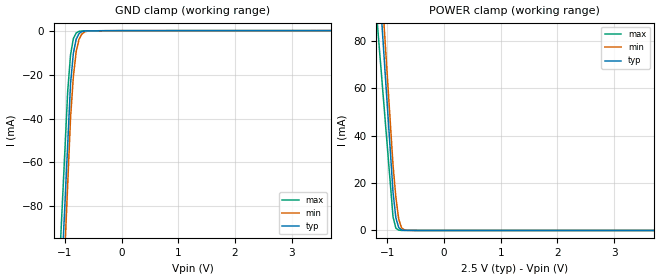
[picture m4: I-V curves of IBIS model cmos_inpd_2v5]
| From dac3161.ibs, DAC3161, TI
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[Model] cmos_inpd_2v5
Model_type Input
Vinl = 625.000mV
Vinh = 1.50000V
C_comp 865.000fF 865.000fF 865.000fF
| variable typ   min   max
[Voltage Range] 2.50000V 2.25000V 2.75000V
[POWER Clamp Reference] 2.50000V 2.25000V 2.75000V
[GND Clamp Reference] 0.00000V 0.00000V 0.00000V
[Temperature Range]   25   85   -40
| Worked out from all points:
|   GND clamp passes 1 mA (typ) near -0.73 V on its own axis
|   POWER clamp passes 1 mA (typ) near -0.79 V on its own axis
[GND Clamp]
-2.5V     -910.4mA   -1.007A    -866.3mA
-950mV    -51.81mA   -69.99mA   -27.77mA
-900mV    -24.11mA   -39.78mA   -11.07mA
-850mV    -10.28mA   -20.91mA   -3.606mA
-800mV    -3.848mA   -9.481mA   -1.049mA
-750mV    -1.297mA   -3.904mA   -310.8uA
-700mV    -414.9uA   -1.507mA   -138.7uA
-600mV    -141uA     -199.2uA   -105.3uA
5V        32.89uA    38.71uA    26.11uA
[POWER Clamp]
-2.5V     594.9mA    624.4mA    476.7mA
-1.15V    106.6mA    120.8mA    79.34mA
-1.1V     88.51mA    102.2mA    64.62mA
-1.05V    70.42mA    83.5mA     49.9mA
-900mV    16.17mA    27.55mA    5.751mA
-850mV    5.321mA    14.01mA    963.3uA
-800mV    1.275mA    4.801mA    157.9uA
-750mV    229.2uA    1.107mA    32.74uA
-700mV    51.51uA    238.1uA    29.47uA
-650mV    44.15uA    58.44uA    26.19uA
5V        0A         0A         0A
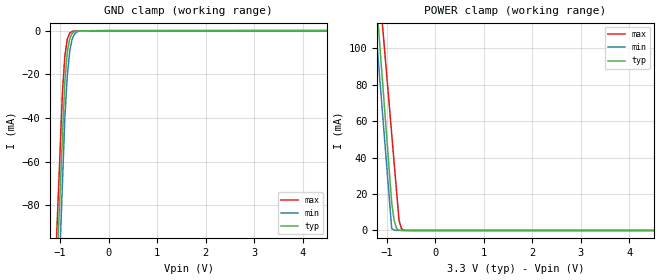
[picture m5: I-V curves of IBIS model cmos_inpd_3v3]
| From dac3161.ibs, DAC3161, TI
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[Model] cmos_inpd_3v3
Model_type Input
Vinl = 750.000mV
Vinh = 1.98000V
C_comp 865.000fF 865.000fF 865.000fF
| variable typ   min   max
[Voltage Range] 3.30000V 3.00000V 3.60000V
[POWER Clamp Reference] 3.30000V 3.00000V 3.60000V
[GND Clamp Reference] 0.00000V 0.00000V 0.00000V
[Temperature Range]   25   85   -40
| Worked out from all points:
|   GND clamp passes 1 mA (typ) near -0.74 V on its own axis
|   POWER clamp passes 1 mA (typ) near -0.79 V on its own axis
[GND Clamp]
-3.3V     -1.265A    -1.499A    -1.32A
-950mV    -49.06mA   -70.33mA   -28.61mA
-900mV    -23.2mA    -39.94mA   -11.61mA
-850mV    -9.95mA    -20.84mA   -3.839mA
-800mV    -3.735mA   -9.456mA   -1.133mA
-750mV    -1.255mA   -3.879mA   -337.2uA
-700mV    -399.4uA   -1.494mA   -148.9uA
-650mV    -154.5uA   -584.3uA   -131.2uA
-600mV    -133.2uA   -198.5uA   -113.5uA
-300mV    -15.44uA   -31.58uA   -24.54uA
6.6V      32.89uA    44.03uA    40.1uA
[POWER Clamp]
-3.3V     861.6mA    803.7mA    808.2mA
-1.05V    68.01mA    51.21mA    100.2mA
-900mV    15.11mA    1.039mA    53mA
-850mV    5.485mA    226.1uA    37.26mA
-800mV    1.108mA    59.56uA    21.53mA
-750mV    188uA      47.65uA    5.794mA
-700mV    34.45uA    35.74uA    996.2uA
-650mV    29.53uA    23.82uA    184.9uA
6.6V      0A         0A         0A
